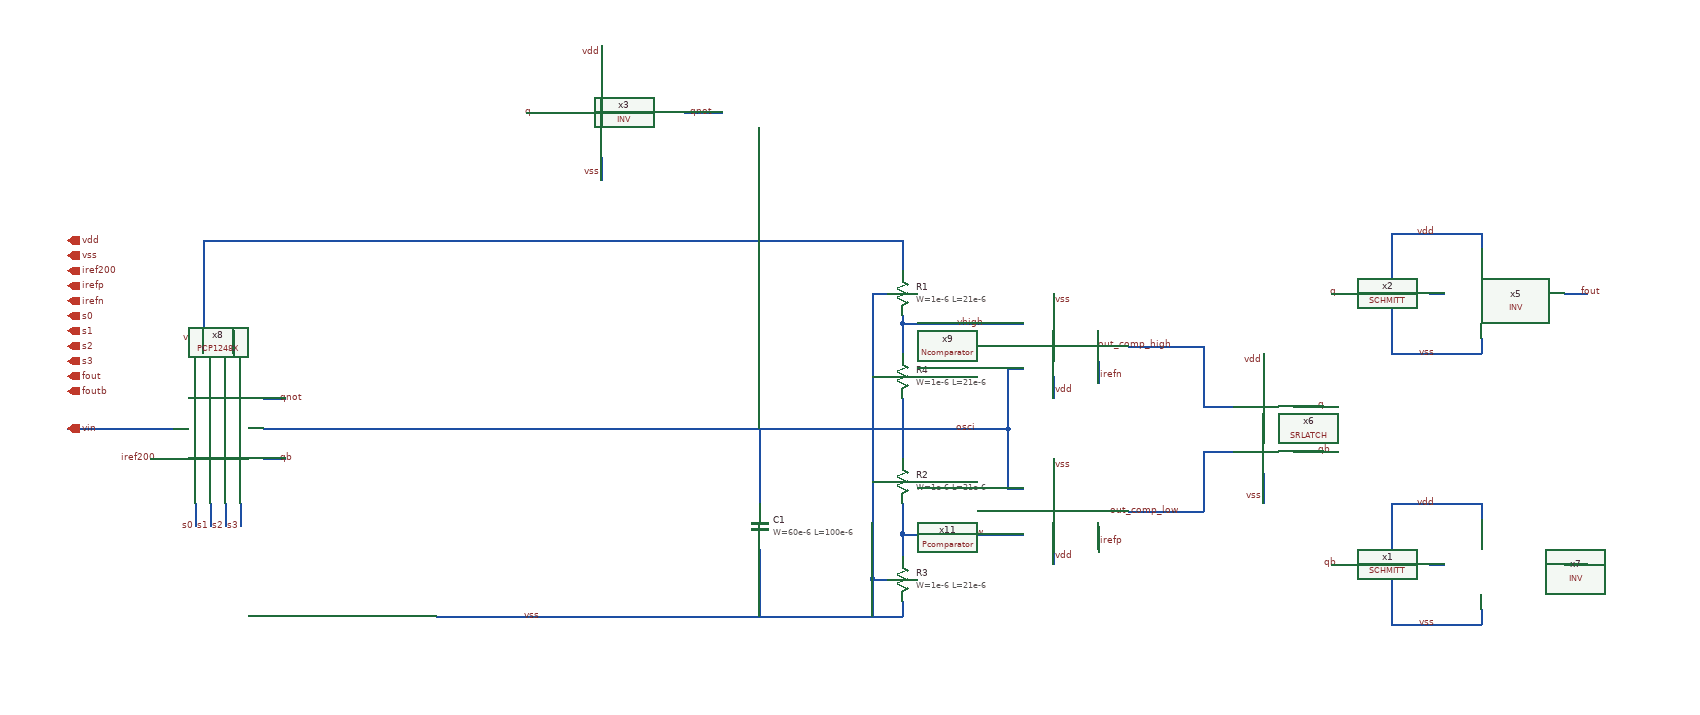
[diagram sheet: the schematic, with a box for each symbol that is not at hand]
v {xschem version=3.4.7 file_version=1.2}
G {}
K {}
V {}
S {}
E {}
N 1490 -540 1490 -510 {lab=vss}
N 1490 -430 1490 -400 {lab=vdd}
N 1490 -320 1490 -290 {lab=vss}
N 1490 -210 1490 -180 {lab=vdd}
N 1690 -390 1730 -390 {lab=out_comp_high}
N 1690 -330 1730 -330 {lab=out_comp_low}
N 1770 -460 1770 -420 {lab=vdd}
N 1770 -300 1770 -260 {lab=vss}
N 1810 -390 1850 -390 {lab=q}
N 1810 -330 1850 -330 {lab=qb}
N 1430 -440 1430 -360 {lab=osci}
N 1430 -440 1450 -440 {lab=osci}
N 1430 -360 1430 -280 {lab=osci}
N 1430 -280 1450 -280 {lab=osci}
N 1690 -470 1690 -390 {lab=out_comp_high}
N 1590 -470 1690 -470 {lab=out_comp_high}
N 1690 -330 1690 -250 {lab=out_comp_low}
N 1590 -250 1690 -250 {lab=out_comp_low}
N 1550 -450 1550 -420 {lab=irefn}
N 1550 -230 1550 -200 {lab=irefp}
N 790 -780 840 -780 {lab=q}
N 1000 -780 1050 -780 {lab=qnot}
N 890 -720 890 -690 {lab=vss}
N 890 -870 890 -840 {lab=vdd}
N 1290 -130 1290 -110 {lab=vss}
N 1990 -540 2010 -540 {lab=#net1}
N 1940 -520 1940 -460 {lab=vss}
N 1940 -460 2060 -460 {lab=vss}
N 2060 -480 2060 -460 {lab=vss}
N 1940 -620 1940 -560 {lab=vdd}
N 1940 -620 2060 -620 {lab=vdd}
N 2060 -620 2060 -600 {lab=vdd}
N 2170 -540 2200 -540 {lab=fout}
N 1860 -540 1890 -540 {lab=q}
N 1990 -180 2010 -180 {lab=#net2}
N 1940 -160 1940 -100 {lab=vss}
N 1940 -100 2060 -100 {lab=vss}
N 2060 -120 2060 -100 {lab=vss}
N 1940 -260 1940 -200 {lab=vdd}
N 1940 -260 2060 -260 {lab=vdd}
N 2060 -260 2060 -240 {lab=vdd}
N 2170 -180 2200 -180 {lab=foutb}
N 1860 -180 1890 -180 {lab=qb}
N 1220 -360 1430 -360 {lab=osci}
N 1290 -220 1290 -190 {lab=vlow}
N 1290 -510 1290 -500 {lab=vhigh}
N 1290 -220 1450 -220 {lab=vlow}
N 1290 -500 1450 -500 {lab=vhigh}
N 1020 -610 1290 -610 {lab=vdd}
N 1290 -610 1290 -570 {lab=vdd}
N 1220 -110 1290 -110 {lab=vss}
N 1010 -110 1220 -110 {lab=vss}
N 290 -360 320 -360 {lab=vin}
N 290 -320 320 -320 {lab=iref200}
N 360 -490 360 -460 {lab=vdd}
N 400 -490 400 -460 {lab=vss}
N 350 -260 350 -230 {lab=s0}
N 370 -260 370 -230 {lab=s1}
N 390 -260 390 -230 {lab=s2}
N 920 -610 1020 -610 {lab=vdd}
N 440 -400 470 -400 {lab=qnot}
N 440 -320 470 -320 {lab=qb}
N 180 -360 290 -360 {lab=vin}
N 780 -610 920 -610 {lab=vdd}
N 800 -110 1010 -110 {lab=vss}
N 1080 -360 1220 -360 {lab=osci}
N 1100 -360 1100 -350 {lab=osci}
N 600 -360 1080 -360 {lab=osci}
N 440 -360 600 -360 {lab=osci}
N 360 -610 780 -610 {lab=vdd}
N 360 -610 360 -490 {lab=vdd}
N 1100 -140 1100 -110 {lab=vss}
N 670 -110 800 -110 {lab=vss}
N 410 -260 410 -230 {lab=s3}
N 1100 -350 1100 -260 {lab=osci}
N 1100 -200 1100 -140 {lab=vss}
N 1290 -500 1290 -460 {lab=vhigh}
N 1290 -400 1290 -320 {lab=#net3}
N 1290 -260 1290 -220 {lab=vlow}
N 1250 -540 1270 -540 {lab=vss}
N 1250 -540 1250 -160 {lab=vss}
N 1250 -160 1270 -160 {lab=vss}
N 1250 -290 1270 -290 {lab=vss}
N 1250 -430 1270 -430 {lab=vss}
N 1250 -160 1250 -110 {lab=vss}
C {lab_wire.sym} 1490 -410 2 0 {name=p4 sig_type=std_logic lab=vdd}
C {lab_wire.sym} 1490 -190 2 0 {name=p5 sig_type=std_logic lab=vdd}
C {lab_wire.sym} 1490 -310 0 1 {name=p6 sig_type=std_logic lab=vss}
C {lab_wire.sym} 1490 -530 0 1 {name=p7 sig_type=std_logic lab=vss}
C {lab_wire.sym} 1400 -220 0 0 {name=p8 sig_type=std_logic lab=vlow}
C {lab_wire.sym} 1400 -500 0 0 {name=p9 sig_type=std_logic lab=vhigh}
C {lab_wire.sym} 1770 -450 0 0 {name=p12 sig_type=std_logic lab=vdd}
C {lab_wire.sym} 1770 -270 2 1 {name=p13 sig_type=std_logic lab=vss}
C {lab_wire.sym} 1840 -390 0 1 {name=p14 sig_type=std_logic lab=q}
C {lab_wire.sym} 1840 -330 0 1 {name=p15 sig_type=std_logic lab=qb}
C {lab_wire.sym} 1390 -360 0 0 {name=p10 sig_type=std_logic lab=osci}
C {lab_wire.sym} 1550 -430 2 0 {name=p23 sig_type=std_logic lab=irefn}
C {lab_wire.sym} 1550 -210 2 0 {name=p26 sig_type=std_logic lab=irefp}
C {lab_wire.sym} 890 -860 0 0 {name=p1 sig_type=std_logic lab=vdd}
C {lab_wire.sym} 890 -700 2 1 {name=p2 sig_type=std_logic lab=vss}
C {lab_wire.sym} 800 -780 0 0 {name=p3 sig_type=std_logic lab=q}
C {lab_wire.sym} 1040 -780 0 0 {name=p16 sig_type=std_logic lab=qnot}
C {lab_wire.sym} 2000 -620 0 0 {name=p21 sig_type=std_logic lab=vdd}
C {lab_wire.sym} 2000 -260 0 0 {name=p22 sig_type=std_logic lab=vdd}
C {lab_wire.sym} 2000 -460 2 1 {name=p38 sig_type=std_logic lab=vss}
C {lab_wire.sym} 2000 -100 2 1 {name=p39 sig_type=std_logic lab=vss}
C {lab_wire.sym} 1870 -540 0 0 {name=p40 sig_type=std_logic lab=q}
C {lab_wire.sym} 1870 -180 0 0 {name=p41 sig_type=std_logic lab=qb}
C {lab_wire.sym} 2190 -540 0 1 {name=p42 sig_type=std_logic lab=fout}
C {lab_wire.sym} 2190 -180 0 1 {name=p43 sig_type=std_logic lab=foutb}
C {libs/qw_core_analog/INV.sym} 900 -650 0 0 {name=x3}
C {libs/qw_core_analog/INV.sym} 2070 -410 0 0 {name=x5}
C {libs/qw_core_analog/INV.sym} 2070 -50 0 0 {name=x7}
C {lab_wire.sym} 1650 -470 0 0 {name=p56 sig_type=std_logic lab=out_comp_high}
C {lab_wire.sym} 1660 -250 0 0 {name=p57 sig_type=std_logic lab=out_comp_low}
C {noconn.sym} 2200 -540 0 1 {name=l2}
C {lab_wire.sym} 300 -320 0 0 {name=p27 sig_type=std_logic lab=iref200}
C {lab_wire.sym} 360 -480 0 0 {name=p28 sig_type=std_logic lab=vdd}
C {lab_wire.sym} 400 -480 0 0 {name=p29 sig_type=std_logic lab=vss}
C {lab_wire.sym} 350 -230 0 0 {name=p30 sig_type=std_logic lab=s0}
C {lab_wire.sym} 370 -230 0 0 {name=p31 sig_type=std_logic lab=s1}
C {lab_wire.sym} 390 -230 0 0 {name=p32 sig_type=std_logic lab=s2}
C {lab_wire.sym} 810 -110 0 0 {name=p33 sig_type=std_logic lab=vss}
C {lab_wire.sym} 460 -320 0 1 {name=p46 sig_type=std_logic lab=qb}
C {lab_wire.sym} 460 -400 0 1 {name=p47 sig_type=std_logic lab=qnot}
C {iopin.sym} 180 -360 0 1 {name=p11 lab=vin}
C {iopin.sym} 180 -610 0 1 {name=p17 lab=vdd}
C {iopin.sym} 180 -590 0 1 {name=p18 lab=vss}
C {iopin.sym} 180 -570 0 1 {name=p19 lab=iref200}
C {iopin.sym} 180 -550 0 1 {name=p20 lab=irefp}
C {iopin.sym} 180 -530 0 1 {name=p24 lab=irefn}
C {iopin.sym} 180 -510 0 1 {name=p25 lab=s0}
C {iopin.sym} 180 -490 0 1 {name=p34 lab=s1}
C {iopin.sym} 180 -470 0 1 {name=p35 lab=s2}
C {iopin.sym} 180 -430 0 1 {name=p36 lab=fout}
C {iopin.sym} 180 -410 0 1 {name=p37 lab=foutb}
C {libs/qw_core_analog/PCP1248X/PCP1248X.sym} 380 -360 0 0 {name=x8}
C {lab_wire.sym} 410 -230 0 0 {name=p44 sig_type=std_logic lab=s3}
C {iopin.sym} 180 -450 0 1 {name=p45 lab=s3}
C {symbols/ppolyf_u.sym} 1290 -160 0 0 {name=R3
W=1e-6
L=21e-6
model=ppolyf_u
spiceprefix=X
m=1}
C {symbols/ppolyf_u.sym} 1290 -540 0 0 {name=R1
W=1e-6
L=21e-6
model=ppolyf_u
spiceprefix=X
m=1}
C {symbols/ppolyf_u.sym} 1290 -290 0 0 {name=R2
W=1e-6
L=21e-6
model=ppolyf_u
spiceprefix=X
m=1}
C {symbols/ppolyf_u.sym} 1290 -430 0 0 {name=R4
W=1e-6
L=21e-6
model=ppolyf_u
spiceprefix=X
m=1}
C {libs/qw_core_analog/SRLATCH/SRLATCH.sym} 1770 -360 0 0 {name=x6}
C {libs/qw_core_analog/Ncomparator/Ncomparator.sym} 1500 -470 2 1 {name=x9}
C {libs/qw_core_analog/Pcomparator/Pcomparator.sym} 1500 -250 2 1 {name=x11}
C {libs/qw_core_analog/SCHMITT/SCHMITT.sym} 1930 -540 0 0 {name=x2}
C {libs/qw_core_analog/SCHMITT/SCHMITT.sym} 1930 -180 0 0 {name=x1}
C {symbols/cap_mim_2f0fF.sym} 1100 -230 0 0 {name=C1
W=60e-6
L=100e-6
model=cap_mim_2f0fF
spiceprefix=X
m=1}
